VERSION 5.7 ;
  NOWIREEXTENSIONATPIN ON ;
  DIVIDERCHAR "/" ;
  BUSBITCHARS "[]" ;
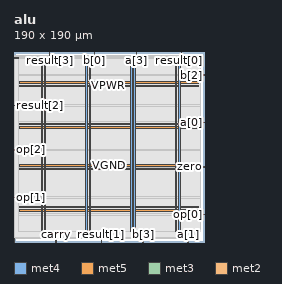
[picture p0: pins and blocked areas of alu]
MACRO alu
  CLASS BLOCK ;
  FOREIGN alu ;
  ORIGIN 0.000 0.000 ;
  SIZE 190.000 BY 190.000 ;
  PIN VGND
    DIRECTION INOUT ;
    USE GROUND ;
    PORT
      LAYER met4 ;
        RECT 30.385 10.640 31.985 177.040 ;
    END
    PORT
      LAYER met4 ;
        RECT 75.120 10.640 76.720 177.040 ;
    END
    PORT
      LAYER met4 ;
        RECT 119.855 10.640 121.455 177.040 ;
    END
    PORT
      LAYER met4 ;
        RECT 164.590 10.640 166.190 177.040 ;
    END
    PORT
      LAYER met5 ;
        RECT 5.280 34.120 184.700 35.720 ;
    END
    PORT
      LAYER met5 ;
        RECT 5.280 75.600 184.700 77.200 ;
    END
    PORT
      LAYER met5 ;
        RECT 5.280 117.080 184.700 118.680 ;
    END
    PORT
      LAYER met5 ;
        RECT 5.280 158.560 184.700 160.160 ;
    END
  END VGND
  PIN VPWR
    DIRECTION INOUT ;
    USE POWER ;
    PORT
      LAYER met4 ;
        RECT 27.085 10.640 28.685 177.040 ;
    END
    PORT
      LAYER met4 ;
        RECT 71.820 10.640 73.420 177.040 ;
    END
    PORT
      LAYER met4 ;
        RECT 116.555 10.640 118.155 177.040 ;
    END
    PORT
      LAYER met4 ;
        RECT 161.290 10.640 162.890 177.040 ;
    END
    PORT
      LAYER met5 ;
        RECT 5.280 30.820 184.700 32.420 ;
    END
    PORT
      LAYER met5 ;
        RECT 5.280 72.300 184.700 73.900 ;
    END
    PORT
      LAYER met5 ;
        RECT 5.280 113.780 184.700 115.380 ;
    END
    PORT
      LAYER met5 ;
        RECT 5.280 155.260 184.700 156.860 ;
    END
  END VPWR
  PIN a[0]
    DIRECTION INPUT ;
    USE SIGNAL ;
    ANTENNAGATEAREA 0.593700 ;
    ANTENNADIFFAREA 0.434700 ;
    PORT
      LAYER met3 ;
        RECT 186.000 119.040 190.000 119.640 ;
    END
  END a[0]
  PIN a[1]
    DIRECTION INPUT ;
    USE SIGNAL ;
    ANTENNAGATEAREA 0.647700 ;
    ANTENNADIFFAREA 0.434700 ;
    PORT
      LAYER met2 ;
        RECT 173.970 0.000 174.250 4.000 ;
    END
  END a[1]
  PIN a[2]
    DIRECTION INPUT ;
    USE SIGNAL ;
    ANTENNAGATEAREA 0.593700 ;
    ANTENNADIFFAREA 0.434700 ;
    PORT
      LAYER met3 ;
        RECT 0.000 183.640 4.000 184.240 ;
    END
  END a[2]
  PIN a[3]
    DIRECTION INPUT ;
    USE SIGNAL ;
    ANTENNAGATEAREA 0.647700 ;
    ANTENNADIFFAREA 0.434700 ;
    PORT
      LAYER met2 ;
        RECT 122.450 186.000 122.730 190.000 ;
    END
  END a[3]
  PIN b[0]
    DIRECTION INPUT ;
    USE SIGNAL ;
    ANTENNAGATEAREA 0.647700 ;
    ANTENNADIFFAREA 0.434700 ;
    PORT
      LAYER met2 ;
        RECT 80.590 186.000 80.870 190.000 ;
    END
  END b[0]
  PIN b[1]
    DIRECTION INPUT ;
    USE SIGNAL ;
    ANTENNAGATEAREA 0.647700 ;
    ANTENNADIFFAREA 0.434700 ;
    PORT
      LAYER met2 ;
        RECT 0.090 0.000 0.370 4.000 ;
    END
  END b[1]
  PIN b[2]
    DIRECTION INPUT ;
    USE SIGNAL ;
    ANTENNAGATEAREA 0.647700 ;
    ANTENNADIFFAREA 0.434700 ;
    PORT
      LAYER met3 ;
        RECT 186.000 166.640 190.000 167.240 ;
    END
  END b[2]
  PIN b[3]
    DIRECTION INPUT ;
    USE SIGNAL ;
    ANTENNAGATEAREA 0.560700 ;
    ANTENNADIFFAREA 0.434700 ;
    PORT
      LAYER met2 ;
        RECT 128.890 0.000 129.170 4.000 ;
    END
  END b[3]
  PIN carry
    DIRECTION OUTPUT TRISTATE ;
    USE SIGNAL ;
    ANTENNADIFFAREA 0.795200 ;
    PORT
      LAYER met2 ;
        RECT 41.950 0.000 42.230 4.000 ;
    END
  END carry
  PIN op[0]
    DIRECTION INPUT ;
    USE SIGNAL ;
    ANTENNAGATEAREA 0.593700 ;
    ANTENNADIFFAREA 0.434700 ;
    PORT
      LAYER met3 ;
        RECT 186.000 27.240 190.000 27.840 ;
    END
  END op[0]
  PIN op[1]
    DIRECTION INPUT ;
    USE SIGNAL ;
    ANTENNAGATEAREA 0.593700 ;
    ANTENNADIFFAREA 0.434700 ;
    PORT
      LAYER met3 ;
        RECT 0.000 44.240 4.000 44.840 ;
    END
  END op[1]
  PIN op[2]
    DIRECTION INPUT ;
    USE SIGNAL ;
    ANTENNAGATEAREA 0.560700 ;
    ANTENNADIFFAREA 0.434700 ;
    PORT
      LAYER met3 ;
        RECT 0.000 91.840 4.000 92.440 ;
    END
  END op[2]
  PIN result[0]
    DIRECTION OUTPUT TRISTATE ;
    USE SIGNAL ;
    ANTENNADIFFAREA 0.795200 ;
    PORT
      LAYER met2 ;
        RECT 167.530 186.000 167.810 190.000 ;
    END
  END result[0]
  PIN result[1]
    DIRECTION OUTPUT TRISTATE ;
    USE SIGNAL ;
    ANTENNADIFFAREA 0.795200 ;
    PORT
      LAYER met2 ;
        RECT 87.030 0.000 87.310 4.000 ;
    END
  END result[1]
  PIN result[2]
    DIRECTION OUTPUT TRISTATE ;
    USE SIGNAL ;
    ANTENNADIFFAREA 0.795200 ;
    PORT
      LAYER met3 ;
        RECT 0.000 136.040 4.000 136.640 ;
    END
  END result[2]
  PIN result[3]
    DIRECTION OUTPUT TRISTATE ;
    USE SIGNAL ;
    ANTENNADIFFAREA 0.795200 ;
    PORT
      LAYER met2 ;
        RECT 35.510 186.000 35.790 190.000 ;
    END
  END result[3]
  PIN zero
    DIRECTION OUTPUT TRISTATE ;
    USE SIGNAL ;
    ANTENNADIFFAREA 0.795200 ;
    PORT
      LAYER met3 ;
        RECT 186.000 74.840 190.000 75.440 ;
    END
  END zero
  OBS
      LAYER li1 ;
        RECT 5.520 10.795 184.460 176.885 ;
      LAYER met1 ;
        RECT 0.070 10.640 184.760 177.040 ;
      LAYER met2 ;
        RECT 0.100 185.720 35.230 186.730 ;
        RECT 36.070 185.720 80.310 186.730 ;
        RECT 81.150 185.720 122.170 186.730 ;
        RECT 123.010 185.720 167.250 186.730 ;
        RECT 168.090 185.720 183.450 186.730 ;
        RECT 0.100 4.280 183.450 185.720 ;
        RECT 0.650 4.000 41.670 4.280 ;
        RECT 42.510 4.000 86.750 4.280 ;
        RECT 87.590 4.000 128.610 4.280 ;
        RECT 129.450 4.000 173.690 4.280 ;
        RECT 174.530 4.000 183.450 4.280 ;
      LAYER met3 ;
        RECT 4.400 183.240 186.000 184.090 ;
        RECT 4.000 167.640 186.000 183.240 ;
        RECT 4.000 166.240 185.600 167.640 ;
        RECT 4.000 137.040 186.000 166.240 ;
        RECT 4.400 135.640 186.000 137.040 ;
        RECT 4.000 120.040 186.000 135.640 ;
        RECT 4.000 118.640 185.600 120.040 ;
        RECT 4.000 92.840 186.000 118.640 ;
        RECT 4.400 91.440 186.000 92.840 ;
        RECT 4.000 75.840 186.000 91.440 ;
        RECT 4.000 74.440 185.600 75.840 ;
        RECT 4.000 45.240 186.000 74.440 ;
        RECT 4.400 43.840 186.000 45.240 ;
        RECT 4.000 28.240 186.000 43.840 ;
        RECT 4.000 26.840 185.600 28.240 ;
        RECT 4.000 10.715 186.000 26.840 ;
  END
END alu
END LIBRARY

